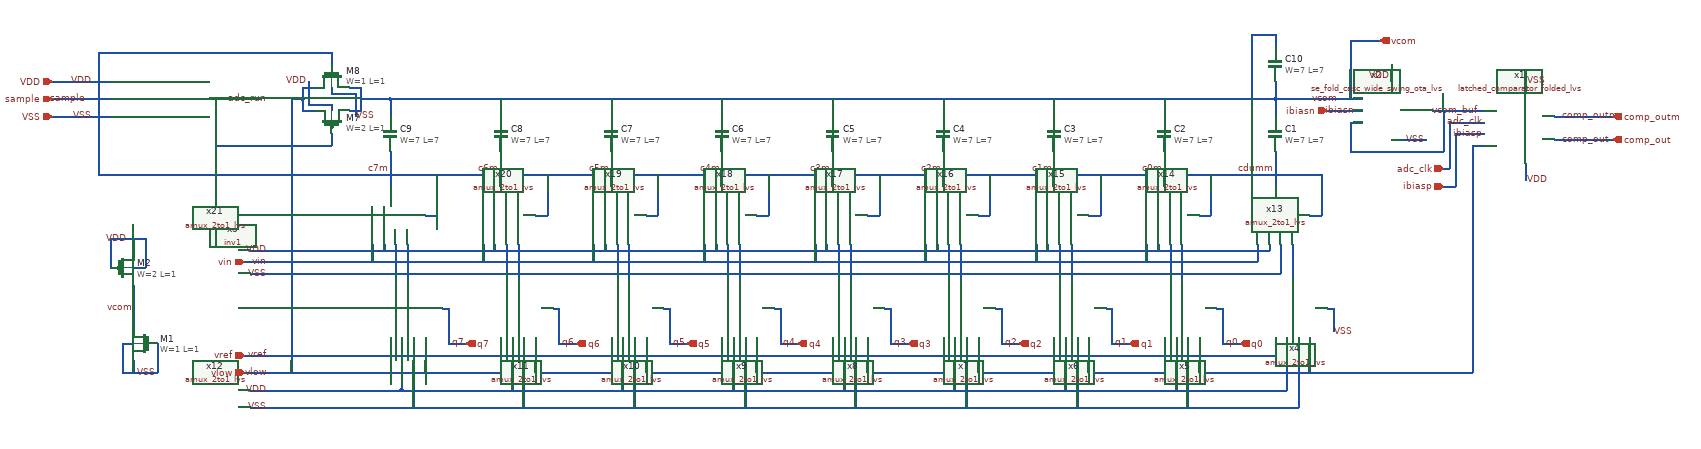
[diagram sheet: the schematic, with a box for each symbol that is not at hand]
v {xschem version=2.9.9 file_version=1.2 }
G {}
K {}
V {}
S {}
E {}
N 810 -780 810 -750 { lab=vcom}
N 810 -780 2330 -780 { lab=vcom}
N 2330 -780 2330 -750 { lab=vcom}
N 2140 -780 2140 -750 { lab=vcom}
N 1950 -780 1950 -750 { lab=vcom}
N 1760 -780 1760 -750 { lab=vcom}
N 1570 -780 1570 -750 { lab=vcom}
N 1380 -780 1380 -750 { lab=vcom}
N 1190 -780 1190 -750 { lab=vcom}
N 1000 -780 1000 -750 { lab=vcom}
N 2330 -780 2480 -780 { lab=vcom}
N 660 -800 660 -780 { lab=vlow}
N 660 -800 680 -800 { lab=vlow}
N 660 -780 660 -760 { lab=vlow}
N 660 -760 680 -760 { lab=vlow}
N 740 -800 760 -800 { lab=vcom}
N 760 -800 760 -760 { lab=vcom}
N 740 -760 760 -760 { lab=vcom}
N 710 -770 710 -760 { lab=VDD}
N 710 -800 710 -790 { lab=VSS}
N 760 -780 810 -780 { lab=vcom}
N 710 -790 750 -790 { lab=VSS}
N 750 -790 750 -750 { lab=VSS}
N 670 -810 670 -770 { lab=VDD}
N 670 -770 710 -770 { lab=VDD}
N 640 -780 660 -780 { lab=vlow}
N 2810 -710 2890 -710 { lab=comp_out}
N 230 -780 330 -780 { lab=sample}
N 490 -780 590 -780 { lab=adc_run}
N 310 -780 310 -650 { lab=sample}
N 310 -650 2410 -650 { lab=sample}
N 840 -530 840 -470 { lab=#net1}
N 1030 -530 1030 -470 { lab=#net2}
N 1220 -530 1220 -470 { lab=#net3}
N 1410 -530 1410 -470 { lab=#net4}
N 1600 -530 1600 -470 { lab=#net5}
N 1790 -530 1790 -470 { lab=#net6}
N 1980 -530 1980 -470 { lab=#net7}
N 2170 -530 2170 -470 { lab=#net8}
N 2360 -530 2360 -470 { lab=#net9}
N 570 -500 2300 -500 { lab=vin}
N 2300 -530 2300 -500 { lab=vin}
N 780 -530 780 -500 { lab=vin}
N 970 -530 970 -500 { lab=vin}
N 1160 -530 1160 -500 { lab=vin}
N 1350 -530 1350 -500 { lab=vin}
N 1540 -530 1540 -500 { lab=vin}
N 1730 -530 1730 -500 { lab=vin}
N 1920 -530 1920 -500 { lab=vin}
N 2110 -530 2110 -500 { lab=vin}
N 2330 -370 2330 -340 { lab=vref}
N 810 -370 810 -340 { lab=vref}
N 1000 -370 1000 -340 { lab=vref}
N 1190 -370 1190 -340 { lab=vref}
N 1380 -370 1380 -340 { lab=vref}
N 1570 -370 1570 -340 { lab=vref}
N 1760 -370 1760 -340 { lab=vref}
N 1950 -370 1950 -340 { lab=vref}
N 2140 -370 2140 -340 { lab=vref}
N 570 -340 2330 -340 { lab=vref}
N 2390 -370 2390 -310 { lab=vlow}
N 2200 -370 2200 -310 { lab=vlow}
N 2010 -370 2010 -310 { lab=vlow}
N 1820 -370 1820 -310 { lab=vlow}
N 1630 -370 1630 -310 { lab=vlow}
N 1440 -370 1440 -310 { lab=vlow}
N 1250 -370 1250 -310 { lab=vlow}
N 1060 -370 1060 -310 { lab=vlow}
N 870 -370 870 -310 { lab=vlow}
N 640 -780 640 -310 { lab=vlow}
N 810 -690 810 -630 { lab=c7m}
N 1000 -690 1000 -630 { lab=c6m}
N 1190 -690 1190 -630 { lab=c5m}
N 1380 -690 1380 -630 { lab=c4m}
N 1570 -690 1570 -630 { lab=c3m}
N 1760 -690 1760 -630 { lab=c2m}
N 1950 -690 1950 -630 { lab=c1m}
N 2140 -690 2140 -630 { lab=c0m}
N 2330 -690 2330 -630 { lab=cdumm}
N 870 -580 890 -580 { lab=sample}
N 890 -650 890 -580 { lab=sample}
N 1060 -580 1080 -580 { lab=sample}
N 1080 -650 1080 -580 { lab=sample}
N 1250 -580 1270 -580 { lab=sample}
N 1270 -650 1270 -580 { lab=sample}
N 1440 -580 1460 -580 { lab=sample}
N 1460 -650 1460 -580 { lab=sample}
N 1630 -580 1650 -580 { lab=sample}
N 1650 -650 1650 -580 { lab=sample}
N 1820 -580 1840 -580 { lab=sample}
N 1840 -650 1840 -580 { lab=sample}
N 2010 -580 2030 -580 { lab=sample}
N 2030 -650 2030 -580 { lab=sample}
N 2200 -580 2220 -580 { lab=sample}
N 2220 -650 2220 -580 { lab=sample}
N 2390 -580 2410 -580 { lab=sample}
N 2410 -650 2410 -580 { lab=sample}
N 910 -360 940 -360 { lab=q7}
N 1100 -360 1130 -360 { lab=q6}
N 1290 -360 1320 -360 { lab=q5}
N 1480 -360 1510 -360 { lab=q4}
N 1670 -360 1700 -360 { lab=q3}
N 1860 -360 1890 -360 { lab=q2}
N 2050 -360 2080 -360 { lab=q1}
N 2240 -360 2270 -360 { lab=q0}
N 900 -420 910 -420 { lab=q7}
N 910 -420 910 -360 { lab=q7}
N 1090 -420 1100 -420 { lab=q6}
N 1100 -420 1100 -360 { lab=q6}
N 1280 -420 1290 -420 { lab=q5}
N 1290 -420 1290 -360 { lab=q5}
N 1470 -420 1480 -420 { lab=q4}
N 1480 -420 1480 -360 { lab=q4}
N 1660 -420 1670 -420 { lab=q3}
N 1670 -420 1670 -360 { lab=q3}
N 1850 -420 1860 -420 { lab=q2}
N 1860 -420 1860 -360 { lab=q2}
N 2040 -420 2050 -420 { lab=q1}
N 2050 -420 2050 -360 { lab=q1}
N 2230 -420 2240 -420 { lab=q0}
N 2240 -420 2240 -360 { lab=q0}
N 310 -860 310 -780 { lab=sample}
N 310 -860 710 -860 { lab=sample}
N 710 -860 710 -840 { lab=sample}
N 510 -780 510 -700 { lab=adc_run}
N 510 -700 710 -700 { lab=adc_run}
N 710 -720 710 -700 { lab=adc_run}
N 2420 -420 2430 -420 { lab=VSS}
N 2430 -420 2430 -380 { lab=VSS}
N 2670 -700 2690 -700 { lab=vlow}
N 2640 -740 2690 -740 { lab=adc_clk}
N 2810 -750 2890 -750 { lab=comp_outm}
N 2460 -740 2480 -740 { lab=vcom_buf}
N 2460 -740 2460 -690 { lab=vcom_buf}
N 2600 -760 2690 -760 { lab=vcom_buf}
N 2460 -690 2620 -690 { lab=vcom_buf}
N 2620 -760 2620 -690 { lab=vcom_buf}
N 2670 -700 2670 -310 { lab=vlow}
N 570 -310 2670 -310 { lab=vlow}
N 270 -810 330 -810 { lab=VDD}
N 270 -750 330 -750 { lab=VSS}
N 2530 -840 2530 -810 { lab=VDD}
N 2530 -710 2590 -710 { lab=VSS}
N 2430 -760 2480 -760 { lab=ibiasn}
N 2760 -830 2760 -790 { lab=VSS}
N 2760 -670 2760 -640 { lab=VDD}
N 2640 -720 2690 -720 { lab=ibiasp}
N 830 -370 830 -280 { lab=VDD}
N 570 -280 830 -280 { lab=VDD}
N 830 -280 2350 -280 { lab=VDD}
N 2350 -370 2350 -280 { lab=VDD}
N 2370 -370 2370 -250 { lab=VSS}
N 570 -250 2370 -250 { lab=VSS}
N 1020 -370 1020 -280 { lab=VDD}
N 1040 -370 1040 -250 { lab=VSS}
N 850 -370 850 -250 { lab=VSS}
N 1210 -370 1210 -280 { lab=VDD}
N 1400 -370 1400 -280 { lab=VDD}
N 1420 -370 1420 -250 { lab=VSS}
N 1230 -370 1230 -250 { lab=VSS}
N 1590 -370 1590 -280 { lab=VDD}
N 1780 -370 1780 -280 { lab=VDD}
N 1800 -370 1800 -250 { lab=VSS}
N 1610 -370 1610 -250 { lab=VSS}
N 1970 -370 1970 -280 { lab=VDD}
N 2160 -370 2160 -280 { lab=VDD}
N 2180 -370 2180 -250 { lab=VSS}
N 1990 -370 1990 -250 { lab=VSS}
N 820 -530 820 -480 { lab=VSS}
N 1010 -530 1010 -480 { lab=VSS}
N 1200 -530 1200 -480 { lab=VSS}
N 1390 -530 1390 -480 { lab=VSS}
N 1580 -530 1580 -480 { lab=VSS}
N 2340 -530 2340 -480 { lab=VSS}
N 2150 -530 2150 -480 { lab=VSS}
N 1960 -530 1960 -480 { lab=VSS}
N 1770 -530 1770 -480 { lab=VSS}
N 570 -480 2340 -480 { lab=VSS}
N 800 -530 800 -520 { lab=VDD}
N 990 -530 990 -520 { lab=VDD}
N 1180 -530 1180 -520 { lab=VDD}
N 1370 -530 1370 -520 { lab=VDD}
N 1560 -530 1560 -520 { lab=VDD}
N 2320 -530 2320 -520 { lab=VDD}
N 2130 -530 2130 -520 { lab=VDD}
N 1940 -530 1940 -520 { lab=VDD}
N 1750 -530 1750 -520 { lab=VDD}
N 570 -520 2320 -520 { lab=VDD}
N 2330 -810 2330 -780 { lab=vcom}
N 2330 -890 2330 -870 { lab=vcom}
N 2290 -890 2330 -890 { lab=vcom}
N 2290 -890 2290 -780 { lab=vcom}
N 370 -460 370 -390 { lab=vcom}
N 370 -490 390 -490 { lab=VDD}
N 390 -540 390 -490 { lab=VDD}
N 370 -540 370 -520 { lab=VDD}
N 330 -540 330 -490 { lab=VDD}
N 330 -540 390 -540 { lab=VDD}
N 350 -360 370 -360 { lab=VSS}
N 350 -360 350 -310 { lab=VSS}
N 370 -330 370 -310 { lab=VSS}
N 410 -360 410 -310 { lab=VSS}
N 350 -310 410 -310 { lab=VSS}
N 230 -810 270 -810 { lab=VDD}
N 230 -750 270 -750 { lab=VSS}
N 560 -310 570 -310 { lab=vlow}
N 560 -340 570 -340 { lab=vref}
N 560 -500 570 -500 { lab=vin}
N 2420 -760 2430 -760 { lab=ibiasn}
N 2640 -720 2640 -660 { lab=ibiasp}
N 2620 -630 2640 -630 { lab=ibiasp}
N 2630 -740 2640 -740 { lab=adc_clk}
N 2630 -740 2630 -670 { lab=adc_clk}
N 2640 -660 2640 -630 { lab=ibiasp}
N 2630 -670 2630 -660 { lab=adc_clk}
N 2620 -660 2630 -660 { lab=adc_clk}
N 2890 -710 2910 -710 { lab=comp_out}
N 2890 -750 2910 -750 { lab=comp_outm}
N 2460 -880 2460 -780 { lab=vcom}
N 2460 -880 2510 -880 { lab=vcom}
C {devices/title.sym} 160 -30 0 0 {name=l1 author="Nikhil Poole"}
C {sky130_fd_pr/pfet_01v8_hvt.sym} 710 -740 3 0 {name=M7
L=1
W=2
nf=1
mult=4
ad="'int((nf+1)/2) * W/nf * 0.29'" 
pd="'2*int((nf+1)/2) * (W/nf + 0.29)'"
as="'int((nf+2)/2) * W/nf * 0.29'" 
ps="'2*int((nf+2)/2) * (W/nf + 0.29)'"
nrd="'0.29 / W'" nrs="'0.29 / W'"
sa=0 sb=0 sd=0
model=pfet_01v8_hvt
spiceprefix=X
}
C {sky130_fd_pr/nfet_01v8.sym} 710 -820 3 1 {name=M8
L=1
W=1
nf=1 
mult=4
ad="'int((nf+1)/2) * W/nf * 0.29'" 
pd="'2*int((nf+1)/2) * (W/nf + 0.29)'"
as="'int((nf+2)/2) * W/nf * 0.29'" 
ps="'2*int((nf+2)/2) * (W/nf + 0.29)'"
nrd="'0.29 / W'" nrs="'0.29 / W'"
sa=0 sb=0 sd=0
model=nfet_01v8
spiceprefix=X
}
C {devices/lab_wire.sym} 530 -780 0 1 {name=l123 sig_type=std_logic lab=adc_run}
C {devices/lab_wire.sym} 2820 -710 0 1 {name=l124 sig_type=std_logic lab=comp_out}
C {devices/lab_wire.sym} 290 -780 0 0 {name=l125 sig_type=std_logic lab=sample}
C {devices/lab_wire.sym} 600 -500 0 0 {name=l7 sig_type=std_logic lab=vin}
C {devices/lab_wire.sym} 600 -340 0 0 {name=l39 sig_type=std_logic lab=vref}
C {devices/lab_wire.sym} 600 -310 0 0 {name=l40 sig_type=std_logic lab=vlow}
C {devices/lab_wire.sym} 940 -360 0 0 {name=l41 sig_type=std_logic lab=q7}
C {devices/lab_wire.sym} 1130 -360 0 0 {name=l42 sig_type=std_logic lab=q6}
C {devices/lab_wire.sym} 1320 -360 0 0 {name=l43 sig_type=std_logic lab=q5}
C {devices/lab_wire.sym} 1510 -360 0 0 {name=l44 sig_type=std_logic lab=q4}
C {devices/lab_wire.sym} 1700 -360 0 0 {name=l45 sig_type=std_logic lab=q3}
C {devices/lab_wire.sym} 1890 -360 0 0 {name=l46 sig_type=std_logic lab=q2}
C {devices/lab_wire.sym} 2080 -360 0 0 {name=l47 sig_type=std_logic lab=q1}
C {devices/lab_wire.sym} 2270 -360 0 0 {name=l48 sig_type=std_logic lab=q0}
C {devices/lab_wire.sym} 810 -660 0 0 {name=l5 sig_type=std_logic lab=c7m}
C {devices/lab_wire.sym} 1000 -660 0 0 {name=l8 sig_type=std_logic lab=c6m}
C {devices/lab_wire.sym} 1190 -660 0 0 {name=l10 sig_type=std_logic lab=c5m}
C {devices/lab_wire.sym} 1380 -660 0 0 {name=l12 sig_type=std_logic lab=c4m}
C {devices/lab_wire.sym} 1570 -660 0 0 {name=l13 sig_type=std_logic lab=c3m}
C {devices/lab_wire.sym} 1760 -660 0 0 {name=l16 sig_type=std_logic lab=c2m}
C {devices/lab_wire.sym} 1950 -660 0 0 {name=l19 sig_type=std_logic lab=c1m}
C {devices/lab_wire.sym} 2140 -660 0 0 {name=l22 sig_type=std_logic lab=c0m}
C {devices/lab_wire.sym} 2330 -660 0 0 {name=l25 sig_type=std_logic lab=cdumm}
C {devices/lab_wire.sym} 2440 -780 0 0 {name=l26 sig_type=std_logic lab=vcom}
C {devices/lab_wire.sym} 2690 -740 0 0 {name=l4 sig_type=std_logic lab=adc_clk}
C {devices/lab_wire.sym} 2820 -750 0 1 {name=l6 sig_type=std_logic lab=comp_outm}
C {devices/lab_wire.sym} 2680 -760 0 0 {name=l3 sig_type=std_logic lab=vcom_buf}
C {/home/users/nhpoole/ee272b/ee272b_mixed_signal_mmwave_accelerator/designs/inv1.sym} 380 -780 0 0 {name=x3}
C {devices/lab_wire.sym} 670 -810 0 0 {name=l9 sig_type=std_logic lab=VDD}
C {devices/lab_wire.sym} 300 -810 0 0 {name=l11 sig_type=std_logic lab=VDD}
C {devices/lab_wire.sym} 300 -750 0 0 {name=l14 sig_type=std_logic lab=VSS}
C {devices/lab_wire.sym} 750 -750 2 0 {name=l15 sig_type=std_logic lab=VSS}
C {/home/users/nhpoole/ee272b/ee272b_mixed_signal_mmwave_accelerator/designs/se_fold_casc_wide_swing_ota_lvs.sym} 2530 -760 0 0 {name=x2}
C {devices/lab_wire.sym} 2530 -820 0 0 {name=l17 sig_type=std_logic lab=VDD}
C {devices/lab_wire.sym} 2590 -710 0 0 {name=l18 sig_type=std_logic lab=VSS}
C {devices/lab_wire.sym} 2470 -760 0 0 {name=l20 sig_type=std_logic lab=ibiasn}
C {/home/users/nhpoole/ee272b/ee272b_mixed_signal_mmwave_accelerator/designs/latched_comparator_folded_lvs.sym} 2750 -730 2 1 {name=x1}
C {devices/lab_wire.sym} 2760 -640 0 1 {name=l21 sig_type=std_logic lab=VDD}
C {devices/lab_wire.sym} 2760 -810 0 1 {name=l23 sig_type=std_logic lab=VSS}
C {devices/lab_wire.sym} 2690 -720 0 0 {name=l24 sig_type=std_logic lab=ibiasp}
C {devices/lab_wire.sym} 2430 -380 0 1 {name=l2 sig_type=std_logic lab=VSS}
C {/home/users/nhpoole/ee272b/ee272b_mixed_signal_mmwave_accelerator/designs/amux_2to1_lvs.sym} 2360 -420 3 0 {name=x4}
C {/home/users/nhpoole/ee272b/ee272b_mixed_signal_mmwave_accelerator/designs/amux_2to1_lvs.sym} 2170 -420 3 0 {name=x5}
C {/home/users/nhpoole/ee272b/ee272b_mixed_signal_mmwave_accelerator/designs/amux_2to1_lvs.sym} 1980 -420 3 0 {name=x6}
C {/home/users/nhpoole/ee272b/ee272b_mixed_signal_mmwave_accelerator/designs/amux_2to1_lvs.sym} 1790 -420 3 0 {name=x7}
C {/home/users/nhpoole/ee272b/ee272b_mixed_signal_mmwave_accelerator/designs/amux_2to1_lvs.sym} 1600 -420 3 0 {name=x8}
C {/home/users/nhpoole/ee272b/ee272b_mixed_signal_mmwave_accelerator/designs/amux_2to1_lvs.sym} 1410 -420 3 0 {name=x9}
C {/home/users/nhpoole/ee272b/ee272b_mixed_signal_mmwave_accelerator/designs/amux_2to1_lvs.sym} 1220 -420 3 0 {name=x10}
C {/home/users/nhpoole/ee272b/ee272b_mixed_signal_mmwave_accelerator/designs/amux_2to1_lvs.sym} 1030 -420 3 0 {name=x11}
C {/home/users/nhpoole/ee272b/ee272b_mixed_signal_mmwave_accelerator/designs/amux_2to1_lvs.sym} 840 -420 3 0 {name=x12}
C {devices/lab_wire.sym} 600 -280 0 0 {name=l27 sig_type=std_logic lab=VDD}
C {devices/lab_wire.sym} 600 -250 0 0 {name=l28 sig_type=std_logic lab=VSS}
C {/home/users/nhpoole/ee272b/ee272b_mixed_signal_mmwave_accelerator/designs/amux_2to1_lvs.sym} 2330 -580 3 0 {name=x13}
C {/home/users/nhpoole/ee272b/ee272b_mixed_signal_mmwave_accelerator/designs/amux_2to1_lvs.sym} 2140 -580 3 0 {name=x14}
C {/home/users/nhpoole/ee272b/ee272b_mixed_signal_mmwave_accelerator/designs/amux_2to1_lvs.sym} 1950 -580 3 0 {name=x15}
C {/home/users/nhpoole/ee272b/ee272b_mixed_signal_mmwave_accelerator/designs/amux_2to1_lvs.sym} 1760 -580 3 0 {name=x16}
C {/home/users/nhpoole/ee272b/ee272b_mixed_signal_mmwave_accelerator/designs/amux_2to1_lvs.sym} 1570 -580 3 0 {name=x17}
C {/home/users/nhpoole/ee272b/ee272b_mixed_signal_mmwave_accelerator/designs/amux_2to1_lvs.sym} 1380 -580 3 0 {name=x18}
C {/home/users/nhpoole/ee272b/ee272b_mixed_signal_mmwave_accelerator/designs/amux_2to1_lvs.sym} 1190 -580 3 0 {name=x19}
C {/home/users/nhpoole/ee272b/ee272b_mixed_signal_mmwave_accelerator/designs/amux_2to1_lvs.sym} 1000 -580 3 0 {name=x20}
C {/home/users/nhpoole/ee272b/ee272b_mixed_signal_mmwave_accelerator/designs/amux_2to1_lvs.sym} 810 -580 3 0 {name=x21}
C {devices/lab_wire.sym} 600 -480 0 0 {name=l29 sig_type=std_logic lab=VSS}
C {devices/lab_wire.sym} 600 -520 0 0 {name=l30 sig_type=std_logic lab=VDD}
C {sky130_fd_pr/cap_mim_m3_1.sym} 2330 -720 0 0 {name=C1 model=cap_mim_m3_1 W=7 L=7 MF=1 spiceprefix=X}
C {sky130_fd_pr/cap_mim_m3_1.sym} 2140 -720 0 0 {name=C2 model=cap_mim_m3_1 W=7 L=7 MF=1 spiceprefix=X}
C {sky130_fd_pr/cap_mim_m3_1.sym} 1950 -720 0 0 {name=C3 model=cap_mim_m3_1 W=7 L=7 MF=2 spiceprefix=X}
C {sky130_fd_pr/cap_mim_m3_1.sym} 1760 -720 0 0 {name=C4 model=cap_mim_m3_1 W=7 L=7 MF=4 spiceprefix=X}
C {sky130_fd_pr/cap_mim_m3_1.sym} 1570 -720 0 0 {name=C5 model=cap_mim_m3_1 W=7 L=7 MF=8 spiceprefix=X}
C {sky130_fd_pr/cap_mim_m3_1.sym} 1380 -720 0 0 {name=C6 model=cap_mim_m3_1 W=7 L=7 MF=16 spiceprefix=X}
C {sky130_fd_pr/cap_mim_m3_1.sym} 1190 -720 0 0 {name=C7 model=cap_mim_m3_1 W=7 L=7 MF=32 spiceprefix=X}
C {sky130_fd_pr/cap_mim_m3_1.sym} 1000 -720 0 0 {name=C8 model=cap_mim_m3_1 W=7 L=7 MF=64 spiceprefix=X}
C {sky130_fd_pr/cap_mim_m3_1.sym} 810 -720 0 0 {name=C9 model=cap_mim_m3_1 W=7 L=7 MF=128 spiceprefix=X}
C {sky130_fd_pr/cap_mim_m3_1.sym} 2330 -840 0 0 {name=C10 model=cap_mim_m3_1 W=7 L=7 MF=68 spiceprefix=X}
C {sky130_fd_pr/nfet_01v8.sym} 390 -360 0 1 {name=M1
L=1
W=1
nf=1 
mult=2
ad="'int((nf+1)/2) * W/nf * 0.29'" 
pd="'2*int((nf+1)/2) * (W/nf + 0.29)'"
as="'int((nf+2)/2) * W/nf * 0.29'" 
ps="'2*int((nf+2)/2) * (W/nf + 0.29)'"
nrd="'0.29 / W'" nrs="'0.29 / W'"
sa=0 sb=0 sd=0
model=nfet_01v8
spiceprefix=X
}
C {sky130_fd_pr/pfet_01v8_hvt.sym} 350 -490 2 1 {name=M2
L=1
W=2
nf=1
mult=2
ad="'int((nf+1)/2) * W/nf * 0.29'" 
pd="'2*int((nf+1)/2) * (W/nf + 0.29)'"
as="'int((nf+2)/2) * W/nf * 0.29'" 
ps="'2*int((nf+2)/2) * (W/nf + 0.29)'"
nrd="'0.29 / W'" nrs="'0.29 / W'"
sa=0 sb=0 sd=0
model=pfet_01v8_hvt
spiceprefix=X
}
C {devices/lab_wire.sym} 410 -310 0 0 {name=l31 sig_type=std_logic lab=VSS}
C {devices/lab_wire.sym} 360 -540 0 0 {name=l32 sig_type=std_logic lab=VDD}
C {devices/ipin.sym} 230 -780 0 0 {name=p1 lab=sample}
C {devices/ipin.sym} 230 -810 0 0 {name=p2 lab=VDD}
C {devices/ipin.sym} 230 -750 0 0 {name=p3 lab=VSS}
C {devices/ipin.sym} 560 -310 0 0 {name=p4 lab=vlow}
C {devices/ipin.sym} 560 -340 0 0 {name=p5 lab=vref}
C {devices/ipin.sym} 560 -500 0 0 {name=p6 lab=vin}
C {devices/ipin.sym} 940 -360 0 1 {name=p7 lab=q7}
C {devices/ipin.sym} 1130 -360 0 1 {name=p8 lab=q6}
C {devices/ipin.sym} 1320 -360 0 1 {name=p9 lab=q5}
C {devices/ipin.sym} 1510 -360 0 1 {name=p10 lab=q4}
C {devices/ipin.sym} 1700 -360 0 1 {name=p11 lab=q3}
C {devices/ipin.sym} 1890 -360 0 1 {name=p12 lab=q2}
C {devices/ipin.sym} 2080 -360 0 1 {name=p13 lab=q1}
C {devices/ipin.sym} 2270 -360 0 1 {name=p14 lab=q0}
C {devices/ipin.sym} 2420 -760 0 0 {name=p15 lab=ibiasn}
C {devices/ipin.sym} 2620 -630 0 0 {name=p16 lab=ibiasp}
C {devices/ipin.sym} 2620 -660 0 0 {name=p17 lab=adc_clk}
C {devices/opin.sym} 2910 -710 0 0 {name=p18 lab=comp_out}
C {devices/opin.sym} 2910 -750 0 0 {name=p19 lab=comp_outm}
C {devices/lab_wire.sym} 370 -420 0 0 {name=l33 sig_type=std_logic lab=vcom}
C {devices/opin.sym} 2510 -880 0 0 {name=p20 lab=vcom}
